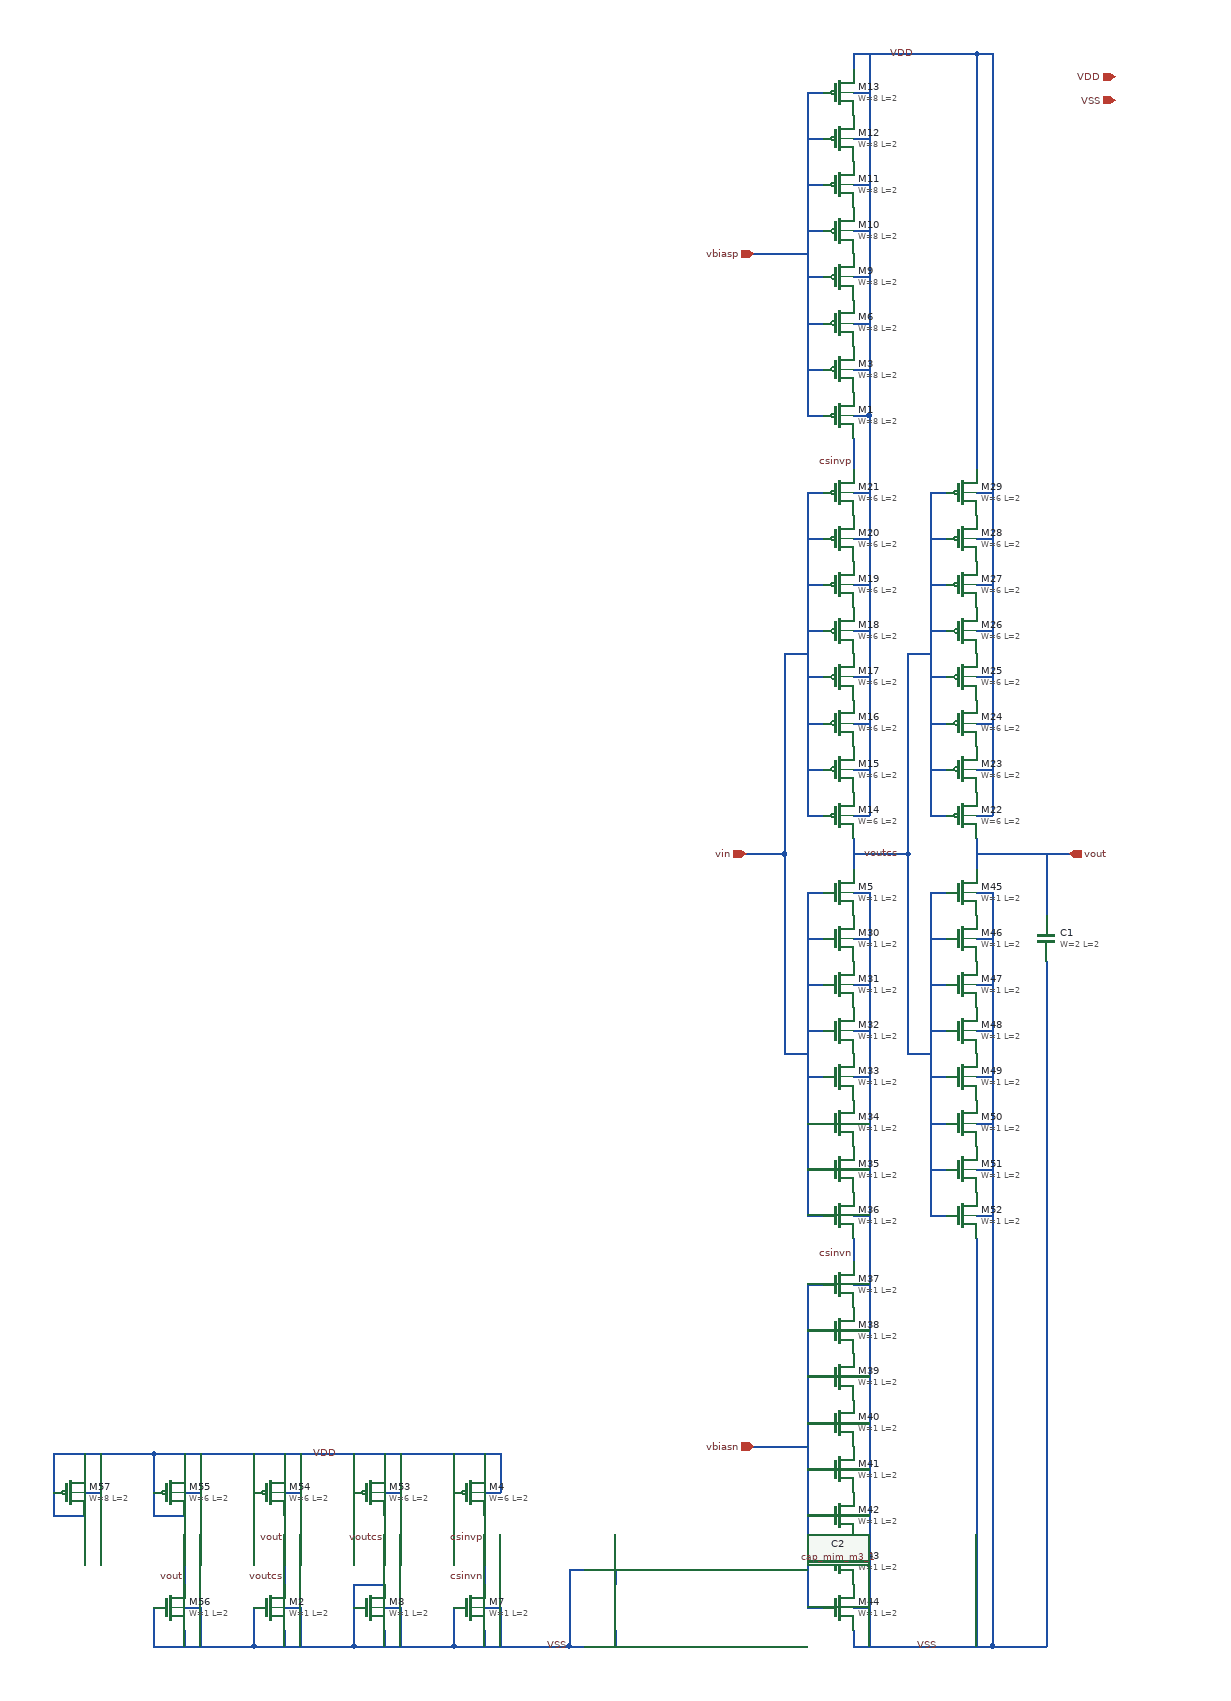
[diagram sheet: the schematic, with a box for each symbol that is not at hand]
v {xschem version=2.9.9 file_version=1.2 

* Copyright 2020 Stefan Frederik Schippers
* 
* Licensed under the Apache License, Version 2.0 (the "License");
* you may not use this file except in compliance with the License.
* You may obtain a copy of the License at
*
*     https://www.apache.org/licenses/LICENSE-2.0
*
* Unless required by applicable law or agreed to in writing, software
* distributed under the License is distributed on an "AS IS" BASIS,
* WITHOUT WARRANTIES OR CONDITIONS OF ANY KIND, either express or implied.
* See the License for the specific language governing permissions and
* limitations under the License.

}
G {}
K {}
V {}
S {}
E {}
N 240 -160 240 -140 { lab=VSS}
N 240 -1120 260 -1120 { lab=VSS}
N 240 -1740 260 -1740 { lab=VDD}
N 100 -1170 150 -1170 { lab=vin}
N 240 -2210 240 -2190 { lab=VDD}
N 110 -1950 180 -1950 { lab=vbiasp}
N 490 -1170 490 -1090 { lab=vout}
N 490 -1030 490 -950 { lab=VSS}
N 240 -1800 260 -1800 { lab=VDD}
N 240 -1860 260 -1860 { lab=VDD}
N 240 -1920 260 -1920 { lab=VDD}
N 240 -1980 260 -1980 { lab=VDD}
N 240 -2040 260 -2040 { lab=VDD}
N 240 -2100 260 -2100 { lab=VDD}
N 240 -2160 260 -2160 { lab=VDD}
N 260 -2210 260 -1740 { lab=VDD}
N 240 -1220 260 -1220 { lab=VDD}
N 240 -1280 260 -1280 { lab=VDD}
N 240 -1340 260 -1340 { lab=VDD}
N 240 -1400 260 -1400 { lab=VDD}
N 240 -1460 260 -1460 { lab=VDD}
N 240 -1520 260 -1520 { lab=VDD}
N 240 -1580 260 -1580 { lab=VDD}
N 240 -1640 260 -1640 { lab=VDD}
N 260 -1690 260 -1220 { lab=VDD}
N 400 -1220 420 -1220 { lab=VDD}
N 400 -1280 420 -1280 { lab=VDD}
N 400 -1340 420 -1340 { lab=VDD}
N 400 -1400 420 -1400 { lab=VDD}
N 400 -1460 420 -1460 { lab=VDD}
N 400 -1520 420 -1520 { lab=VDD}
N 400 -1580 420 -1580 { lab=VDD}
N 400 -1640 420 -1640 { lab=VDD}
N 420 -1690 420 -1220 { lab=VDD}
N 240 -1060 260 -1060 { lab=VSS}
N 240 -1000 260 -1000 { lab=VSS}
N 240 -940 260 -940 { lab=VSS}
N 240 -880 260 -880 { lab=VSS}
N 240 -820 260 -820 { lab=VSS}
N 240 -760 260 -760 { lab=VSS}
N 240 -700 260 -700 { lab=VSS}
N 240 -610 260 -610 { lab=VSS}
N 240 -550 260 -550 { lab=VSS}
N 240 -490 260 -490 { lab=VSS}
N 240 -430 260 -430 { lab=VSS}
N 240 -370 260 -370 { lab=VSS}
N 240 -310 260 -310 { lab=VSS}
N 240 -250 260 -250 { lab=VSS}
N 240 -190 260 -190 { lab=VSS}
N 240 -670 240 -640 { lab=csinvn}
N 260 -1120 260 -140 { lab=VSS}
N 400 -1120 420 -1120 { lab=VSS}
N 400 -1060 420 -1060 { lab=VSS}
N 400 -1000 420 -1000 { lab=VSS}
N 400 -940 420 -940 { lab=VSS}
N 400 -880 420 -880 { lab=VSS}
N 400 -820 420 -820 { lab=VSS}
N 400 -760 420 -760 { lab=VSS}
N 400 -700 420 -700 { lab=VSS}
N 400 -1190 400 -1150 { lab=vout}
N 400 -1170 520 -1170 { lab=vout}
N 240 -1710 240 -1670 { lab=csinvp}
N 260 -1740 260 -1690 { lab=VDD}
N 240 -2210 390 -2210 { lab=VDD}
N 400 -2210 400 -1670 { lab=VDD}
N 390 -2210 400 -2210 { lab=VDD}
N 420 -2210 420 -1690 { lab=VDD}
N 400 -2210 420 -2210 { lab=VDD}
N 340 -1120 360 -1120 { lab=voutcs}
N 340 -1120 340 -700 { lab=voutcs}
N 340 -700 360 -700 { lab=voutcs}
N 340 -760 360 -760 { lab=voutcs}
N 340 -820 360 -820 { lab=voutcs}
N 340 -880 360 -880 { lab=voutcs}
N 340 -940 360 -940 { lab=voutcs}
N 340 -1000 360 -1000 { lab=voutcs}
N 340 -1060 360 -1060 { lab=voutcs}
N 340 -1640 360 -1640 { lab=voutcs}
N 340 -1640 340 -1220 { lab=voutcs}
N 340 -1220 360 -1220 { lab=voutcs}
N 340 -1280 360 -1280 { lab=voutcs}
N 340 -1340 360 -1340 { lab=voutcs}
N 340 -1400 360 -1400 { lab=voutcs}
N 340 -1460 360 -1460 { lab=voutcs}
N 340 -1520 360 -1520 { lab=voutcs}
N 340 -1580 360 -1580 { lab=voutcs}
N 180 -1640 200 -1640 { lab=vin}
N 180 -1640 180 -1220 { lab=vin}
N 180 -1220 200 -1220 { lab=vin}
N 180 -1280 200 -1280 { lab=vin}
N 180 -1340 200 -1340 { lab=vin}
N 180 -1400 200 -1400 { lab=vin}
N 180 -1460 200 -1460 { lab=vin}
N 180 -1520 200 -1520 { lab=vin}
N 180 -1580 200 -1580 { lab=vin}
N 180 -2160 200 -2160 { lab=vbiasp}
N 180 -2160 180 -1740 { lab=vbiasp}
N 180 -1740 200 -1740 { lab=vbiasp}
N 180 -1800 200 -1800 { lab=vbiasp}
N 180 -1860 200 -1860 { lab=vbiasp}
N 180 -1920 200 -1920 { lab=vbiasp}
N 180 -1980 200 -1980 { lab=vbiasp}
N 180 -2040 200 -2040 { lab=vbiasp}
N 180 -2100 200 -2100 { lab=vbiasp}
N 180 -610 200 -610 { lab=vbiasn}
N 180 -610 180 -190 { lab=vbiasn}
N 180 -190 200 -190 { lab=vbiasn}
N 180 -250 200 -250 { lab=vbiasn}
N 180 -310 200 -310 { lab=vbiasn}
N 180 -370 200 -370 { lab=vbiasn}
N 180 -430 200 -430 { lab=vbiasn}
N 180 -490 200 -490 { lab=vbiasn}
N 180 -550 200 -550 { lab=vbiasn}
N 180 -1120 200 -1120 { lab=vin}
N 180 -1120 180 -700 { lab=vin}
N 180 -700 200 -700 { lab=vin}
N 180 -760 200 -760 { lab=vin}
N 180 -820 200 -820 { lab=vin}
N 180 -880 200 -880 { lab=vin}
N 180 -940 200 -940 { lab=vin}
N 180 -1000 200 -1000 { lab=vin}
N 180 -1060 200 -1060 { lab=vin}
N 110 -400 180 -400 { lab=vbiasn}
N 240 -1190 240 -1150 { lab=voutcs}
N 420 -1120 420 -140 { lab=VSS}
N 240 -140 420 -140 { lab=VSS}
N 400 -670 400 -140 { lab=VSS}
N 490 -950 490 -140 { lab=VSS}
N 420 -140 490 -140 { lab=VSS}
N 150 -1430 150 -1170 { lab=vin}
N 150 -1430 180 -1430 { lab=vin}
N 150 -1170 150 -910 { lab=vin}
N 150 -910 180 -910 { lab=vin}
N 240 -1170 310 -1170 { lab=voutcs}
N 310 -1430 310 -1170 { lab=voutcs}
N 310 -1430 340 -1430 { lab=voutcs}
N 310 -1170 310 -910 { lab=voutcs}
N 310 -910 340 -910 { lab=voutcs}
N -70 -240 -70 -220 { lab=VSS}
N -130 -240 -110 -240 { lab=VSS}
N -130 -240 -130 -150 { lab=VSS}
N -130 -150 -130 -140 { lab=VSS}
N -130 -140 -110 -140 { lab=VSS}
N -70 -160 -70 -140 { lab=VSS}
N -240 -190 -220 -190 { lab=VSS}
N -220 -190 -220 -140 { lab=VSS}
N -280 -190 -280 -140 { lab=VSS}
N -240 -160 -240 -140 { lab=VSS}
N -240 -250 -240 -220 { lab=csinvn}
N -280 -140 -130 -140 { lab=VSS}
N -370 -190 -350 -190 { lab=VSS}
N -350 -190 -350 -140 { lab=VSS}
N -370 -160 -370 -140 { lab=VSS}
N -410 -190 -410 -140 { lab=VSS}
N -410 -220 -370 -220 { lab=VSS}
N -410 -220 -410 -190 { lab=VSS}
N -410 -140 -280 -140 { lab=VSS}
N -500 -190 -480 -190 { lab=VSS}
N -480 -190 -480 -140 { lab=VSS}
N -500 -160 -500 -140 { lab=VSS}
N -540 -190 -540 -140 { lab=VSS}
N -500 -250 -500 -220 { lab=voutcs}
N -540 -140 -410 -140 { lab=VSS}
N -240 -310 -240 -280 { lab=csinvp}
N -240 -340 -220 -340 { lab=VDD}
N -220 -390 -220 -340 { lab=VDD}
N -240 -390 -240 -370 { lab=VDD}
N -280 -390 -280 -340 { lab=VDD}
N -370 -310 -370 -280 { lab=voutcs}
N -370 -340 -350 -340 { lab=VDD}
N -350 -390 -350 -340 { lab=VDD}
N -370 -390 -370 -370 { lab=VDD}
N -410 -390 -410 -340 { lab=VDD}
N -500 -310 -500 -280 { lab=vout}
N -500 -340 -480 -340 { lab=VDD}
N -480 -390 -480 -340 { lab=VDD}
N -500 -390 -500 -370 { lab=VDD}
N -540 -390 -540 -340 { lab=VDD}
N -630 -340 -610 -340 { lab=VDD}
N -610 -390 -610 -340 { lab=VDD}
N -630 -390 -630 -370 { lab=VDD}
N -670 -390 -670 -340 { lab=VDD}
N -670 -310 -630 -310 { lab=VDD}
N -670 -340 -670 -310 { lab=VDD}
N -670 -390 -220 -390 { lab=VDD}
N -630 -190 -610 -190 { lab=VSS}
N -610 -190 -610 -140 { lab=VSS}
N -630 -160 -630 -140 { lab=VSS}
N -670 -190 -670 -140 { lab=VSS}
N -630 -250 -630 -220 { lab=vout}
N -670 -140 -540 -140 { lab=VSS}
N -760 -340 -740 -340 { lab=VDD}
N -740 -390 -740 -340 { lab=VDD}
N -760 -390 -760 -370 { lab=VDD}
N -800 -390 -800 -340 { lab=VDD}
N -800 -310 -760 -310 { lab=VDD}
N -800 -340 -800 -310 { lab=VDD}
N -800 -390 -670 -390 { lab=VDD}
C {devices/title.sym} 160 -30 0 0 {name=l1 author="Nikhil Poole"}
C {sky130_fd_pr/nfet_01v8.sym} 220 -1120 0 0 {name=M5
L=2
W=1
nf=1 
mult=1
ad="'int((nf+1)/2) * W/nf * 0.29'" 
pd="'2*int((nf+1)/2) * (W/nf + 0.29)'"
as="'int((nf+2)/2) * W/nf * 0.29'" 
ps="'2*int((nf+2)/2) * (W/nf + 0.29)'"
nrd="'0.29 / W'" nrs="'0.29 / W'"
sa=0 sb=0 sd=0
model=nfet_01v8
spiceprefix=X
}
C {sky130_fd_pr/pfet_01v8_hvt.sym} 220 -1740 0 0 {name=M1
L=2
W=8
nf=1
mult=2
ad="'int((nf+1)/2) * W/nf * 0.29'" 
pd="'2*int((nf+1)/2) * (W/nf + 0.29)'"
as="'int((nf+2)/2) * W/nf * 0.29'" 
ps="'2*int((nf+2)/2) * (W/nf + 0.29)'"
nrd="'0.29 / W'" nrs="'0.29 / W'"
sa=0 sb=0 sd=0
model=pfet_01v8_hvt
spiceprefix=X
}
C {devices/opin.sym} 520 -1170 0 0 {name=p1 lab=vout}
C {devices/ipin.sym} 100 -1170 0 0 {name=p2 lab=vin}
C {devices/ipin.sym} 110 -400 0 0 {name=p3 lab=vbiasn}
C {devices/ipin.sym} 110 -1950 0 0 {name=p4 lab=vbiasp}
C {sky130_fd_pr/cap_mim_m3_1.sym} 490 -1060 0 0 {name=C1 model=cap_mim_m3_1 W=2 L=2 MF=9 spiceprefix=X}
C {devices/lab_wire.sym} 320 -2210 0 0 {name=l2 sig_type=std_logic lab=VDD}
C {devices/lab_wire.sym} 350 -140 0 0 {name=l3 sig_type=std_logic lab=VSS}
C {sky130_fd_pr/pfet_01v8_hvt.sym} 220 -1800 0 0 {name=M3
L=2
W=8
nf=1
mult=2
ad="'int((nf+1)/2) * W/nf * 0.29'" 
pd="'2*int((nf+1)/2) * (W/nf + 0.29)'"
as="'int((nf+2)/2) * W/nf * 0.29'" 
ps="'2*int((nf+2)/2) * (W/nf + 0.29)'"
nrd="'0.29 / W'" nrs="'0.29 / W'"
sa=0 sb=0 sd=0
model=pfet_01v8_hvt
spiceprefix=X
}
C {sky130_fd_pr/pfet_01v8_hvt.sym} 220 -1860 0 0 {name=M6
L=2
W=8
nf=1
mult=2
ad="'int((nf+1)/2) * W/nf * 0.29'" 
pd="'2*int((nf+1)/2) * (W/nf + 0.29)'"
as="'int((nf+2)/2) * W/nf * 0.29'" 
ps="'2*int((nf+2)/2) * (W/nf + 0.29)'"
nrd="'0.29 / W'" nrs="'0.29 / W'"
sa=0 sb=0 sd=0
model=pfet_01v8_hvt
spiceprefix=X
}
C {sky130_fd_pr/pfet_01v8_hvt.sym} 220 -1920 0 0 {name=M9
L=2
W=8
nf=1
mult=2
ad="'int((nf+1)/2) * W/nf * 0.29'" 
pd="'2*int((nf+1)/2) * (W/nf + 0.29)'"
as="'int((nf+2)/2) * W/nf * 0.29'" 
ps="'2*int((nf+2)/2) * (W/nf + 0.29)'"
nrd="'0.29 / W'" nrs="'0.29 / W'"
sa=0 sb=0 sd=0
model=pfet_01v8_hvt
spiceprefix=X
}
C {sky130_fd_pr/pfet_01v8_hvt.sym} 220 -1980 0 0 {name=M10
L=2
W=8
nf=1
mult=2
ad="'int((nf+1)/2) * W/nf * 0.29'" 
pd="'2*int((nf+1)/2) * (W/nf + 0.29)'"
as="'int((nf+2)/2) * W/nf * 0.29'" 
ps="'2*int((nf+2)/2) * (W/nf + 0.29)'"
nrd="'0.29 / W'" nrs="'0.29 / W'"
sa=0 sb=0 sd=0
model=pfet_01v8_hvt
spiceprefix=X
}
C {sky130_fd_pr/pfet_01v8_hvt.sym} 220 -2040 0 0 {name=M11
L=2
W=8
nf=1
mult=2
ad="'int((nf+1)/2) * W/nf * 0.29'" 
pd="'2*int((nf+1)/2) * (W/nf + 0.29)'"
as="'int((nf+2)/2) * W/nf * 0.29'" 
ps="'2*int((nf+2)/2) * (W/nf + 0.29)'"
nrd="'0.29 / W'" nrs="'0.29 / W'"
sa=0 sb=0 sd=0
model=pfet_01v8_hvt
spiceprefix=X
}
C {sky130_fd_pr/pfet_01v8_hvt.sym} 220 -2100 0 0 {name=M12
L=2
W=8
nf=1
mult=2
ad="'int((nf+1)/2) * W/nf * 0.29'" 
pd="'2*int((nf+1)/2) * (W/nf + 0.29)'"
as="'int((nf+2)/2) * W/nf * 0.29'" 
ps="'2*int((nf+2)/2) * (W/nf + 0.29)'"
nrd="'0.29 / W'" nrs="'0.29 / W'"
sa=0 sb=0 sd=0
model=pfet_01v8_hvt
spiceprefix=X
}
C {sky130_fd_pr/pfet_01v8_hvt.sym} 220 -2160 0 0 {name=M13
L=2
W=8
nf=1
mult=2
ad="'int((nf+1)/2) * W/nf * 0.29'" 
pd="'2*int((nf+1)/2) * (W/nf + 0.29)'"
as="'int((nf+2)/2) * W/nf * 0.29'" 
ps="'2*int((nf+2)/2) * (W/nf + 0.29)'"
nrd="'0.29 / W'" nrs="'0.29 / W'"
sa=0 sb=0 sd=0
model=pfet_01v8_hvt
spiceprefix=X
}
C {sky130_fd_pr/pfet_01v8_hvt.sym} 220 -1220 0 0 {name=M14
L=2
W=6
nf=1
mult=1
ad="'int((nf+1)/2) * W/nf * 0.29'" 
pd="'2*int((nf+1)/2) * (W/nf + 0.29)'"
as="'int((nf+2)/2) * W/nf * 0.29'" 
ps="'2*int((nf+2)/2) * (W/nf + 0.29)'"
nrd="'0.29 / W'" nrs="'0.29 / W'"
sa=0 sb=0 sd=0
model=pfet_01v8_hvt
spiceprefix=X
}
C {sky130_fd_pr/pfet_01v8_hvt.sym} 220 -1280 0 0 {name=M15
L=2
W=6
nf=1
mult=1
ad="'int((nf+1)/2) * W/nf * 0.29'" 
pd="'2*int((nf+1)/2) * (W/nf + 0.29)'"
as="'int((nf+2)/2) * W/nf * 0.29'" 
ps="'2*int((nf+2)/2) * (W/nf + 0.29)'"
nrd="'0.29 / W'" nrs="'0.29 / W'"
sa=0 sb=0 sd=0
model=pfet_01v8_hvt
spiceprefix=X
}
C {sky130_fd_pr/pfet_01v8_hvt.sym} 220 -1340 0 0 {name=M16
L=2
W=6
nf=1
mult=1
ad="'int((nf+1)/2) * W/nf * 0.29'" 
pd="'2*int((nf+1)/2) * (W/nf + 0.29)'"
as="'int((nf+2)/2) * W/nf * 0.29'" 
ps="'2*int((nf+2)/2) * (W/nf + 0.29)'"
nrd="'0.29 / W'" nrs="'0.29 / W'"
sa=0 sb=0 sd=0
model=pfet_01v8_hvt
spiceprefix=X
}
C {sky130_fd_pr/pfet_01v8_hvt.sym} 220 -1400 0 0 {name=M17
L=2
W=6
nf=1
mult=1
ad="'int((nf+1)/2) * W/nf * 0.29'" 
pd="'2*int((nf+1)/2) * (W/nf + 0.29)'"
as="'int((nf+2)/2) * W/nf * 0.29'" 
ps="'2*int((nf+2)/2) * (W/nf + 0.29)'"
nrd="'0.29 / W'" nrs="'0.29 / W'"
sa=0 sb=0 sd=0
model=pfet_01v8_hvt
spiceprefix=X
}
C {sky130_fd_pr/pfet_01v8_hvt.sym} 220 -1460 0 0 {name=M18
L=2
W=6
nf=1
mult=1
ad="'int((nf+1)/2) * W/nf * 0.29'" 
pd="'2*int((nf+1)/2) * (W/nf + 0.29)'"
as="'int((nf+2)/2) * W/nf * 0.29'" 
ps="'2*int((nf+2)/2) * (W/nf + 0.29)'"
nrd="'0.29 / W'" nrs="'0.29 / W'"
sa=0 sb=0 sd=0
model=pfet_01v8_hvt
spiceprefix=X
}
C {sky130_fd_pr/pfet_01v8_hvt.sym} 220 -1520 0 0 {name=M19
L=2
W=6
nf=1
mult=1
ad="'int((nf+1)/2) * W/nf * 0.29'" 
pd="'2*int((nf+1)/2) * (W/nf + 0.29)'"
as="'int((nf+2)/2) * W/nf * 0.29'" 
ps="'2*int((nf+2)/2) * (W/nf + 0.29)'"
nrd="'0.29 / W'" nrs="'0.29 / W'"
sa=0 sb=0 sd=0
model=pfet_01v8_hvt
spiceprefix=X
}
C {sky130_fd_pr/pfet_01v8_hvt.sym} 220 -1580 0 0 {name=M20
L=2
W=6
nf=1
mult=1
ad="'int((nf+1)/2) * W/nf * 0.29'" 
pd="'2*int((nf+1)/2) * (W/nf + 0.29)'"
as="'int((nf+2)/2) * W/nf * 0.29'" 
ps="'2*int((nf+2)/2) * (W/nf + 0.29)'"
nrd="'0.29 / W'" nrs="'0.29 / W'"
sa=0 sb=0 sd=0
model=pfet_01v8_hvt
spiceprefix=X
}
C {sky130_fd_pr/pfet_01v8_hvt.sym} 220 -1640 0 0 {name=M21
L=2
W=6
nf=1
mult=1
ad="'int((nf+1)/2) * W/nf * 0.29'" 
pd="'2*int((nf+1)/2) * (W/nf + 0.29)'"
as="'int((nf+2)/2) * W/nf * 0.29'" 
ps="'2*int((nf+2)/2) * (W/nf + 0.29)'"
nrd="'0.29 / W'" nrs="'0.29 / W'"
sa=0 sb=0 sd=0
model=pfet_01v8_hvt
spiceprefix=X
}
C {sky130_fd_pr/pfet_01v8_hvt.sym} 380 -1220 0 0 {name=M22
L=2
W=6
nf=1
mult=1
ad="'int((nf+1)/2) * W/nf * 0.29'" 
pd="'2*int((nf+1)/2) * (W/nf + 0.29)'"
as="'int((nf+2)/2) * W/nf * 0.29'" 
ps="'2*int((nf+2)/2) * (W/nf + 0.29)'"
nrd="'0.29 / W'" nrs="'0.29 / W'"
sa=0 sb=0 sd=0
model=pfet_01v8_hvt
spiceprefix=X
}
C {sky130_fd_pr/pfet_01v8_hvt.sym} 380 -1280 0 0 {name=M23
L=2
W=6
nf=1
mult=1
ad="'int((nf+1)/2) * W/nf * 0.29'" 
pd="'2*int((nf+1)/2) * (W/nf + 0.29)'"
as="'int((nf+2)/2) * W/nf * 0.29'" 
ps="'2*int((nf+2)/2) * (W/nf + 0.29)'"
nrd="'0.29 / W'" nrs="'0.29 / W'"
sa=0 sb=0 sd=0
model=pfet_01v8_hvt
spiceprefix=X
}
C {sky130_fd_pr/pfet_01v8_hvt.sym} 380 -1340 0 0 {name=M24
L=2
W=6
nf=1
mult=1
ad="'int((nf+1)/2) * W/nf * 0.29'" 
pd="'2*int((nf+1)/2) * (W/nf + 0.29)'"
as="'int((nf+2)/2) * W/nf * 0.29'" 
ps="'2*int((nf+2)/2) * (W/nf + 0.29)'"
nrd="'0.29 / W'" nrs="'0.29 / W'"
sa=0 sb=0 sd=0
model=pfet_01v8_hvt
spiceprefix=X
}
C {sky130_fd_pr/pfet_01v8_hvt.sym} 380 -1400 0 0 {name=M25
L=2
W=6
nf=1
mult=1
ad="'int((nf+1)/2) * W/nf * 0.29'" 
pd="'2*int((nf+1)/2) * (W/nf + 0.29)'"
as="'int((nf+2)/2) * W/nf * 0.29'" 
ps="'2*int((nf+2)/2) * (W/nf + 0.29)'"
nrd="'0.29 / W'" nrs="'0.29 / W'"
sa=0 sb=0 sd=0
model=pfet_01v8_hvt
spiceprefix=X
}
C {sky130_fd_pr/pfet_01v8_hvt.sym} 380 -1460 0 0 {name=M26
L=2
W=6
nf=1
mult=1
ad="'int((nf+1)/2) * W/nf * 0.29'" 
pd="'2*int((nf+1)/2) * (W/nf + 0.29)'"
as="'int((nf+2)/2) * W/nf * 0.29'" 
ps="'2*int((nf+2)/2) * (W/nf + 0.29)'"
nrd="'0.29 / W'" nrs="'0.29 / W'"
sa=0 sb=0 sd=0
model=pfet_01v8_hvt
spiceprefix=X
}
C {sky130_fd_pr/pfet_01v8_hvt.sym} 380 -1520 0 0 {name=M27
L=2
W=6
nf=1
mult=1
ad="'int((nf+1)/2) * W/nf * 0.29'" 
pd="'2*int((nf+1)/2) * (W/nf + 0.29)'"
as="'int((nf+2)/2) * W/nf * 0.29'" 
ps="'2*int((nf+2)/2) * (W/nf + 0.29)'"
nrd="'0.29 / W'" nrs="'0.29 / W'"
sa=0 sb=0 sd=0
model=pfet_01v8_hvt
spiceprefix=X
}
C {sky130_fd_pr/pfet_01v8_hvt.sym} 380 -1580 0 0 {name=M28
L=2
W=6
nf=1
mult=1
ad="'int((nf+1)/2) * W/nf * 0.29'" 
pd="'2*int((nf+1)/2) * (W/nf + 0.29)'"
as="'int((nf+2)/2) * W/nf * 0.29'" 
ps="'2*int((nf+2)/2) * (W/nf + 0.29)'"
nrd="'0.29 / W'" nrs="'0.29 / W'"
sa=0 sb=0 sd=0
model=pfet_01v8_hvt
spiceprefix=X
}
C {sky130_fd_pr/pfet_01v8_hvt.sym} 380 -1640 0 0 {name=M29
L=2
W=6
nf=1
mult=1
ad="'int((nf+1)/2) * W/nf * 0.29'" 
pd="'2*int((nf+1)/2) * (W/nf + 0.29)'"
as="'int((nf+2)/2) * W/nf * 0.29'" 
ps="'2*int((nf+2)/2) * (W/nf + 0.29)'"
nrd="'0.29 / W'" nrs="'0.29 / W'"
sa=0 sb=0 sd=0
model=pfet_01v8_hvt
spiceprefix=X
}
C {sky130_fd_pr/nfet_01v8.sym} 220 -1060 0 0 {name=M30
L=2
W=1
nf=1 
mult=1
ad="'int((nf+1)/2) * W/nf * 0.29'" 
pd="'2*int((nf+1)/2) * (W/nf + 0.29)'"
as="'int((nf+2)/2) * W/nf * 0.29'" 
ps="'2*int((nf+2)/2) * (W/nf + 0.29)'"
nrd="'0.29 / W'" nrs="'0.29 / W'"
sa=0 sb=0 sd=0
model=nfet_01v8
spiceprefix=X
}
C {sky130_fd_pr/nfet_01v8.sym} 220 -1000 0 0 {name=M31
L=2
W=1
nf=1 
mult=1
ad="'int((nf+1)/2) * W/nf * 0.29'" 
pd="'2*int((nf+1)/2) * (W/nf + 0.29)'"
as="'int((nf+2)/2) * W/nf * 0.29'" 
ps="'2*int((nf+2)/2) * (W/nf + 0.29)'"
nrd="'0.29 / W'" nrs="'0.29 / W'"
sa=0 sb=0 sd=0
model=nfet_01v8
spiceprefix=X
}
C {sky130_fd_pr/nfet_01v8.sym} 220 -940 0 0 {name=M32
L=2
W=1
nf=1 
mult=1
ad="'int((nf+1)/2) * W/nf * 0.29'" 
pd="'2*int((nf+1)/2) * (W/nf + 0.29)'"
as="'int((nf+2)/2) * W/nf * 0.29'" 
ps="'2*int((nf+2)/2) * (W/nf + 0.29)'"
nrd="'0.29 / W'" nrs="'0.29 / W'"
sa=0 sb=0 sd=0
model=nfet_01v8
spiceprefix=X
}
C {sky130_fd_pr/nfet_01v8.sym} 220 -880 0 0 {name=M33
L=2
W=1
nf=1 
mult=1
ad="'int((nf+1)/2) * W/nf * 0.29'" 
pd="'2*int((nf+1)/2) * (W/nf + 0.29)'"
as="'int((nf+2)/2) * W/nf * 0.29'" 
ps="'2*int((nf+2)/2) * (W/nf + 0.29)'"
nrd="'0.29 / W'" nrs="'0.29 / W'"
sa=0 sb=0 sd=0
model=nfet_01v8
spiceprefix=X
}
C {sky130_fd_pr/nfet_01v8.sym} 220 -820 0 0 {name=M34
L=2
W=1
nf=1 
mult=1
ad="'int((nf+1)/2) * W/nf * 0.29'" 
pd="'2*int((nf+1)/2) * (W/nf + 0.29)'"
as="'int((nf+2)/2) * W/nf * 0.29'" 
ps="'2*int((nf+2)/2) * (W/nf + 0.29)'"
nrd="'0.29 / W'" nrs="'0.29 / W'"
sa=0 sb=0 sd=0
model=nfet_01v8
spiceprefix=X
}
C {sky130_fd_pr/nfet_01v8.sym} 220 -760 0 0 {name=M35
L=2
W=1
nf=1 
mult=1
ad="'int((nf+1)/2) * W/nf * 0.29'" 
pd="'2*int((nf+1)/2) * (W/nf + 0.29)'"
as="'int((nf+2)/2) * W/nf * 0.29'" 
ps="'2*int((nf+2)/2) * (W/nf + 0.29)'"
nrd="'0.29 / W'" nrs="'0.29 / W'"
sa=0 sb=0 sd=0
model=nfet_01v8
spiceprefix=X
}
C {sky130_fd_pr/nfet_01v8.sym} 220 -700 0 0 {name=M36
L=2
W=1
nf=1 
mult=1
ad="'int((nf+1)/2) * W/nf * 0.29'" 
pd="'2*int((nf+1)/2) * (W/nf + 0.29)'"
as="'int((nf+2)/2) * W/nf * 0.29'" 
ps="'2*int((nf+2)/2) * (W/nf + 0.29)'"
nrd="'0.29 / W'" nrs="'0.29 / W'"
sa=0 sb=0 sd=0
model=nfet_01v8
spiceprefix=X
}
C {sky130_fd_pr/nfet_01v8.sym} 220 -610 0 0 {name=M37
L=2
W=1
nf=1 
mult=1
ad="'int((nf+1)/2) * W/nf * 0.29'" 
pd="'2*int((nf+1)/2) * (W/nf + 0.29)'"
as="'int((nf+2)/2) * W/nf * 0.29'" 
ps="'2*int((nf+2)/2) * (W/nf + 0.29)'"
nrd="'0.29 / W'" nrs="'0.29 / W'"
sa=0 sb=0 sd=0
model=nfet_01v8
spiceprefix=X
}
C {sky130_fd_pr/nfet_01v8.sym} 220 -550 0 0 {name=M38
L=2
W=1
nf=1 
mult=1
ad="'int((nf+1)/2) * W/nf * 0.29'" 
pd="'2*int((nf+1)/2) * (W/nf + 0.29)'"
as="'int((nf+2)/2) * W/nf * 0.29'" 
ps="'2*int((nf+2)/2) * (W/nf + 0.29)'"
nrd="'0.29 / W'" nrs="'0.29 / W'"
sa=0 sb=0 sd=0
model=nfet_01v8
spiceprefix=X
}
C {sky130_fd_pr/nfet_01v8.sym} 220 -490 0 0 {name=M39
L=2
W=1
nf=1 
mult=1
ad="'int((nf+1)/2) * W/nf * 0.29'" 
pd="'2*int((nf+1)/2) * (W/nf + 0.29)'"
as="'int((nf+2)/2) * W/nf * 0.29'" 
ps="'2*int((nf+2)/2) * (W/nf + 0.29)'"
nrd="'0.29 / W'" nrs="'0.29 / W'"
sa=0 sb=0 sd=0
model=nfet_01v8
spiceprefix=X
}
C {sky130_fd_pr/nfet_01v8.sym} 220 -430 0 0 {name=M40
L=2
W=1
nf=1 
mult=1
ad="'int((nf+1)/2) * W/nf * 0.29'" 
pd="'2*int((nf+1)/2) * (W/nf + 0.29)'"
as="'int((nf+2)/2) * W/nf * 0.29'" 
ps="'2*int((nf+2)/2) * (W/nf + 0.29)'"
nrd="'0.29 / W'" nrs="'0.29 / W'"
sa=0 sb=0 sd=0
model=nfet_01v8
spiceprefix=X
}
C {sky130_fd_pr/nfet_01v8.sym} 220 -370 0 0 {name=M41
L=2
W=1
nf=1 
mult=1
ad="'int((nf+1)/2) * W/nf * 0.29'" 
pd="'2*int((nf+1)/2) * (W/nf + 0.29)'"
as="'int((nf+2)/2) * W/nf * 0.29'" 
ps="'2*int((nf+2)/2) * (W/nf + 0.29)'"
nrd="'0.29 / W'" nrs="'0.29 / W'"
sa=0 sb=0 sd=0
model=nfet_01v8
spiceprefix=X
}
C {sky130_fd_pr/nfet_01v8.sym} 220 -310 0 0 {name=M42
L=2
W=1
nf=1 
mult=1
ad="'int((nf+1)/2) * W/nf * 0.29'" 
pd="'2*int((nf+1)/2) * (W/nf + 0.29)'"
as="'int((nf+2)/2) * W/nf * 0.29'" 
ps="'2*int((nf+2)/2) * (W/nf + 0.29)'"
nrd="'0.29 / W'" nrs="'0.29 / W'"
sa=0 sb=0 sd=0
model=nfet_01v8
spiceprefix=X
}
C {sky130_fd_pr/nfet_01v8.sym} 220 -250 0 0 {name=M43
L=2
W=1
nf=1 
mult=1
ad="'int((nf+1)/2) * W/nf * 0.29'" 
pd="'2*int((nf+1)/2) * (W/nf + 0.29)'"
as="'int((nf+2)/2) * W/nf * 0.29'" 
ps="'2*int((nf+2)/2) * (W/nf + 0.29)'"
nrd="'0.29 / W'" nrs="'0.29 / W'"
sa=0 sb=0 sd=0
model=nfet_01v8
spiceprefix=X
}
C {sky130_fd_pr/nfet_01v8.sym} 220 -190 0 0 {name=M44
L=2
W=1
nf=1 
mult=1
ad="'int((nf+1)/2) * W/nf * 0.29'" 
pd="'2*int((nf+1)/2) * (W/nf + 0.29)'"
as="'int((nf+2)/2) * W/nf * 0.29'" 
ps="'2*int((nf+2)/2) * (W/nf + 0.29)'"
nrd="'0.29 / W'" nrs="'0.29 / W'"
sa=0 sb=0 sd=0
model=nfet_01v8
spiceprefix=X
}
C {sky130_fd_pr/nfet_01v8.sym} 380 -1120 0 0 {name=M45
L=2
W=1
nf=1 
mult=1
ad="'int((nf+1)/2) * W/nf * 0.29'" 
pd="'2*int((nf+1)/2) * (W/nf + 0.29)'"
as="'int((nf+2)/2) * W/nf * 0.29'" 
ps="'2*int((nf+2)/2) * (W/nf + 0.29)'"
nrd="'0.29 / W'" nrs="'0.29 / W'"
sa=0 sb=0 sd=0
model=nfet_01v8
spiceprefix=X
}
C {sky130_fd_pr/nfet_01v8.sym} 380 -1060 0 0 {name=M46
L=2
W=1
nf=1 
mult=1
ad="'int((nf+1)/2) * W/nf * 0.29'" 
pd="'2*int((nf+1)/2) * (W/nf + 0.29)'"
as="'int((nf+2)/2) * W/nf * 0.29'" 
ps="'2*int((nf+2)/2) * (W/nf + 0.29)'"
nrd="'0.29 / W'" nrs="'0.29 / W'"
sa=0 sb=0 sd=0
model=nfet_01v8
spiceprefix=X
}
C {sky130_fd_pr/nfet_01v8.sym} 380 -1000 0 0 {name=M47
L=2
W=1
nf=1 
mult=1
ad="'int((nf+1)/2) * W/nf * 0.29'" 
pd="'2*int((nf+1)/2) * (W/nf + 0.29)'"
as="'int((nf+2)/2) * W/nf * 0.29'" 
ps="'2*int((nf+2)/2) * (W/nf + 0.29)'"
nrd="'0.29 / W'" nrs="'0.29 / W'"
sa=0 sb=0 sd=0
model=nfet_01v8
spiceprefix=X
}
C {sky130_fd_pr/nfet_01v8.sym} 380 -940 0 0 {name=M48
L=2
W=1
nf=1 
mult=1
ad="'int((nf+1)/2) * W/nf * 0.29'" 
pd="'2*int((nf+1)/2) * (W/nf + 0.29)'"
as="'int((nf+2)/2) * W/nf * 0.29'" 
ps="'2*int((nf+2)/2) * (W/nf + 0.29)'"
nrd="'0.29 / W'" nrs="'0.29 / W'"
sa=0 sb=0 sd=0
model=nfet_01v8
spiceprefix=X
}
C {sky130_fd_pr/nfet_01v8.sym} 380 -880 0 0 {name=M49
L=2
W=1
nf=1 
mult=1
ad="'int((nf+1)/2) * W/nf * 0.29'" 
pd="'2*int((nf+1)/2) * (W/nf + 0.29)'"
as="'int((nf+2)/2) * W/nf * 0.29'" 
ps="'2*int((nf+2)/2) * (W/nf + 0.29)'"
nrd="'0.29 / W'" nrs="'0.29 / W'"
sa=0 sb=0 sd=0
model=nfet_01v8
spiceprefix=X
}
C {sky130_fd_pr/nfet_01v8.sym} 380 -820 0 0 {name=M50
L=2
W=1
nf=1 
mult=1
ad="'int((nf+1)/2) * W/nf * 0.29'" 
pd="'2*int((nf+1)/2) * (W/nf + 0.29)'"
as="'int((nf+2)/2) * W/nf * 0.29'" 
ps="'2*int((nf+2)/2) * (W/nf + 0.29)'"
nrd="'0.29 / W'" nrs="'0.29 / W'"
sa=0 sb=0 sd=0
model=nfet_01v8
spiceprefix=X
}
C {sky130_fd_pr/nfet_01v8.sym} 380 -760 0 0 {name=M51
L=2
W=1
nf=1 
mult=1
ad="'int((nf+1)/2) * W/nf * 0.29'" 
pd="'2*int((nf+1)/2) * (W/nf + 0.29)'"
as="'int((nf+2)/2) * W/nf * 0.29'" 
ps="'2*int((nf+2)/2) * (W/nf + 0.29)'"
nrd="'0.29 / W'" nrs="'0.29 / W'"
sa=0 sb=0 sd=0
model=nfet_01v8
spiceprefix=X
}
C {sky130_fd_pr/nfet_01v8.sym} 380 -700 0 0 {name=M52
L=2
W=1
nf=1 
mult=1
ad="'int((nf+1)/2) * W/nf * 0.29'" 
pd="'2*int((nf+1)/2) * (W/nf + 0.29)'"
as="'int((nf+2)/2) * W/nf * 0.29'" 
ps="'2*int((nf+2)/2) * (W/nf + 0.29)'"
nrd="'0.29 / W'" nrs="'0.29 / W'"
sa=0 sb=0 sd=0
model=nfet_01v8
spiceprefix=X
}
C {devices/ipin.sym} 580 -2180 0 0 {name=p5 lab=VDD}
C {devices/ipin.sym} 580 -2150 0 0 {name=p6 lab=VSS}
C {sky130_fd_pr/cap_mim_m3_1.sym} -110 -190 0 0 {name=C2 model=cap_mim_m3_1 W=2 L=2 MF=16 spiceprefix=X}
C {devices/lab_wire.sym} -130 -140 0 0 {name=l7 sig_type=std_logic lab=VSS}
C {sky130_fd_pr/nfet_01v8.sym} -260 -190 0 0 {name=M7
L=2
W=1
nf=1
mult=2
ad="'int((nf+1)/2) * W/nf * 0.29'" 
pd="'2*int((nf+1)/2) * (W/nf + 0.29)'"
as="'int((nf+2)/2) * W/nf * 0.29'" 
ps="'2*int((nf+2)/2) * (W/nf + 0.29)'"
nrd="'0.29 / W'" nrs="'0.29 / W'"
sa=0 sb=0 sd=0
model=nfet_01v8
spiceprefix=X
}
C {devices/lab_wire.sym} -240 -230 0 0 {name=l10 sig_type=std_logic lab=csinvn}
C {sky130_fd_pr/nfet_01v8.sym} -390 -190 0 0 {name=M8
L=2
W=1
nf=1
mult=2
ad="'int((nf+1)/2) * W/nf * 0.29'" 
pd="'2*int((nf+1)/2) * (W/nf + 0.29)'"
as="'int((nf+2)/2) * W/nf * 0.29'" 
ps="'2*int((nf+2)/2) * (W/nf + 0.29)'"
nrd="'0.29 / W'" nrs="'0.29 / W'"
sa=0 sb=0 sd=0
model=nfet_01v8
spiceprefix=X
}
C {sky130_fd_pr/nfet_01v8.sym} -520 -190 0 0 {name=M2
L=2
W=1
nf=1
mult=1
ad="'int((nf+1)/2) * W/nf * 0.29'" 
pd="'2*int((nf+1)/2) * (W/nf + 0.29)'"
as="'int((nf+2)/2) * W/nf * 0.29'" 
ps="'2*int((nf+2)/2) * (W/nf + 0.29)'"
nrd="'0.29 / W'" nrs="'0.29 / W'"
sa=0 sb=0 sd=0
model=nfet_01v8
spiceprefix=X
}
C {devices/lab_wire.sym} -500 -230 0 0 {name=l11 sig_type=std_logic lab=voutcs}
C {devices/lab_wire.sym} -240 -280 0 0 {name=l12 sig_type=std_logic lab=csinvp}
C {devices/lab_wire.sym} -370 -280 0 0 {name=l13 sig_type=std_logic lab=voutcs}
C {devices/lab_wire.sym} -500 -280 0 0 {name=l14 sig_type=std_logic lab=vout}
C {devices/lab_wire.sym} -430 -390 0 0 {name=l15 sig_type=std_logic lab=VDD}
C {sky130_fd_pr/nfet_01v8.sym} -650 -190 0 0 {name=M56
L=2
W=1
nf=1
mult=1
ad="'int((nf+1)/2) * W/nf * 0.29'" 
pd="'2*int((nf+1)/2) * (W/nf + 0.29)'"
as="'int((nf+2)/2) * W/nf * 0.29'" 
ps="'2*int((nf+2)/2) * (W/nf + 0.29)'"
nrd="'0.29 / W'" nrs="'0.29 / W'"
sa=0 sb=0 sd=0
model=nfet_01v8
spiceprefix=X
}
C {devices/lab_wire.sym} -630 -230 0 0 {name=l16 sig_type=std_logic lab=vout}
C {devices/lab_wire.sym} 240 -650 0 0 {name=l4 sig_type=std_logic lab=csinvn}
C {devices/lab_wire.sym} 240 -1680 0 0 {name=l5 sig_type=std_logic lab=csinvp}
C {devices/lab_wire.sym} 300 -1170 0 0 {name=l6 sig_type=std_logic lab=voutcs}
C {sky130_fd_pr/pfet_01v8_hvt.sym} -260 -340 0 0 {name=M4
L=2
W=6
nf=1
mult=1
ad="'int((nf+1)/2) * W/nf * 0.29'" 
pd="'2*int((nf+1)/2) * (W/nf + 0.29)'"
as="'int((nf+2)/2) * W/nf * 0.29'" 
ps="'2*int((nf+2)/2) * (W/nf + 0.29)'"
nrd="'0.29 / W'" nrs="'0.29 / W'"
sa=0 sb=0 sd=0
model=pfet_01v8_hvt
spiceprefix=X
}
C {sky130_fd_pr/pfet_01v8_hvt.sym} -390 -340 0 0 {name=M53
L=2
W=6
nf=1
mult=1
ad="'int((nf+1)/2) * W/nf * 0.29'" 
pd="'2*int((nf+1)/2) * (W/nf + 0.29)'"
as="'int((nf+2)/2) * W/nf * 0.29'" 
ps="'2*int((nf+2)/2) * (W/nf + 0.29)'"
nrd="'0.29 / W'" nrs="'0.29 / W'"
sa=0 sb=0 sd=0
model=pfet_01v8_hvt
spiceprefix=X
}
C {sky130_fd_pr/pfet_01v8_hvt.sym} -520 -340 0 0 {name=M54
L=2
W=6
nf=1
mult=1
ad="'int((nf+1)/2) * W/nf * 0.29'" 
pd="'2*int((nf+1)/2) * (W/nf + 0.29)'"
as="'int((nf+2)/2) * W/nf * 0.29'" 
ps="'2*int((nf+2)/2) * (W/nf + 0.29)'"
nrd="'0.29 / W'" nrs="'0.29 / W'"
sa=0 sb=0 sd=0
model=pfet_01v8_hvt
spiceprefix=X
}
C {sky130_fd_pr/pfet_01v8_hvt.sym} -650 -340 0 0 {name=M55
L=2
W=6
nf=1
mult=1
ad="'int((nf+1)/2) * W/nf * 0.29'" 
pd="'2*int((nf+1)/2) * (W/nf + 0.29)'"
as="'int((nf+2)/2) * W/nf * 0.29'" 
ps="'2*int((nf+2)/2) * (W/nf + 0.29)'"
nrd="'0.29 / W'" nrs="'0.29 / W'"
sa=0 sb=0 sd=0
model=pfet_01v8_hvt
spiceprefix=X
}
C {sky130_fd_pr/pfet_01v8_hvt.sym} -780 -340 0 0 {name=M57
L=2
W=8
nf=1
mult=2
ad="'int((nf+1)/2) * W/nf * 0.29'" 
pd="'2*int((nf+1)/2) * (W/nf + 0.29)'"
as="'int((nf+2)/2) * W/nf * 0.29'" 
ps="'2*int((nf+2)/2) * (W/nf + 0.29)'"
nrd="'0.29 / W'" nrs="'0.29 / W'"
sa=0 sb=0 sd=0
model=pfet_01v8_hvt
spiceprefix=X
}
